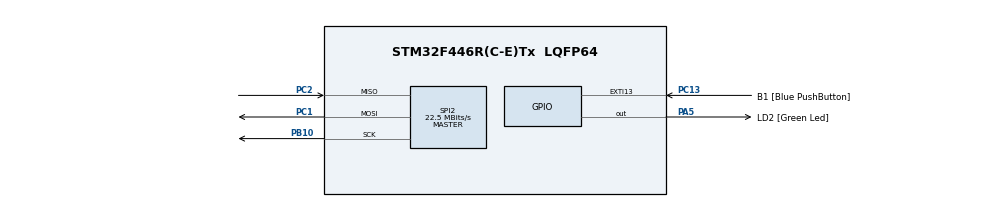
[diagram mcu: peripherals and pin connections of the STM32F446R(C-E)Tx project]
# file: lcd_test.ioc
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Dma.Request0=SPI2_TX
Dma.SPI2_TX.0.Direction=DMA_MEMORY_TO_PERIPH
Dma.SPI2_TX.0.FIFOMode=DMA_FIFOMODE_DISABLE
Dma.SPI2_TX.0.Instance=DMA1_Stream4
Dma.SPI2_TX.0.MemDataAlignment=DMA_MDATAALIGN_HALFWORD
Dma.SPI2_TX.0.MemInc=DMA_MINC_ENABLE
Dma.SPI2_TX.0.Mode=DMA_NORMAL
Dma.SPI2_TX.0.PeriphDataAlignment=DMA_PDATAALIGN_HALFWORD
Dma.SPI2_TX.0.PeriphInc=DMA_PINC_DISABLE
Dma.SPI2_TX.0.Priority=DMA_PRIORITY_MEDIUM
Mcu.Family=STM32F4
Mcu.Name=STM32F446R(C-E)Tx
Mcu.Package=LQFP64
NVIC.DMA1_Stream4_IRQn=true\:0\:0\:false\:false\:true
NVIC.PriorityGroup=NVIC_PRIORITYGROUP_0
PA13.GPIO_Label=TMS
PA13.Signal=SYS_JTMS-SWDIO
PA14.GPIO_Label=TCK
PA14.Signal=SYS_JTCK-SWCLK
PA2.GPIO_Label=USART_TX
PA2.Signal=USART2_TX
PA3.GPIO_Label=USART_RX
PA3.Signal=USART2_RX
PA5.GPIO_Label=LD2 [Green Led]
PA5.Signal=GPIO_Output
PB10.Mode=Full_Duplex_Master
PB10.Signal=SPI2_SCK
PB3.GPIO_Label=SWO
PB3.Signal=SYS_JTDO-SWO
PC1.Mode=Full_Duplex_Master
PC1.Signal=SPI2_MOSI
PC13.GPIO_Label=B1 [Blue PushButton]
PC13.GPIO_ModeDefaultEXTI=GPIO_MODE_IT_FALLING
PC13.Signal=GPXTI13
PC14-OSC32_IN.Signal=RCC_OSC32_IN
PC15-OSC32_OUT.Signal=RCC_OSC32_OUT
PC2.Mode=Full_Duplex_Master
PC2.Signal=SPI2_MISO
PH0-OSC_IN.Signal=RCC_OSC_IN
PH1-OSC_OUT.Signal=RCC_OSC_OUT
ProjectManager.HeapSize=0x200
ProjectManager.StackSize=0x400
ProjectManager.TargetToolchain=SW4STM32
RCC.AHBFreq_Value=180000000
RCC.APB1CLKDivider=RCC_HCLK_DIV4
RCC.APB1Freq_Value=45000000
RCC.APB1TimFreq_Value=90000000
RCC.APB2CLKDivider=RCC_HCLK_DIV2
RCC.APB2Freq_Value=90000000
RCC.APB2TimFreq_Value=180000000
RCC.CortexFreq_Value=180000000
RCC.FLatency-AdvancedSettings=FLASH_LATENCY_5
RCC.HCLKFreq_Value=180000000
RCC.HSE_VALUE=8000000
RCC.HSI_VALUE=16000000
RCC.LSE_VALUE=32768
RCC.PLLM=8
RCC.PLLN=180
RCC.SYSCLKFreq_VALUE=180000000
RCC.SYSCLKSource=RCC_SYSCLKSOURCE_PLLCLK
RCC.USBFreq_Value=180000000
RCC.VCOOutputFreq_Value=360000000
SPI2.BaudRatePrescaler=SPI_BAUDRATEPRESCALER_2
SPI2.CalculateBaudRate=22.5 MBits/s
SPI2.DataSize=SPI_DATASIZE_16BIT
SPI2.Direction=SPI_DIRECTION_2LINES
SPI2.Mode=SPI_MODE_MASTER
SPI2.VirtualType=VM_MASTER
board=NUCLEO-F446RE

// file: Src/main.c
/**
  ******************************************************************************
  * File Name          : main.c
  * Description        : Main program body
  ******************************************************************************
  *
  * COPYRIGHT(c) 2017 STMicroelectronics
  *
  * Redistribution and use in source and binary forms, with or without modification,
  * are permitted provided that the following conditions are met:
  *   1. Redistributions of source code must retain the above copyright notice,
  *      this list of conditions and the following disclaimer.
  *   2. Redistributions in binary form must reproduce the above copyright notice,
  *      this list of conditions and the following disclaimer in the documentation
  *      and/or other materials provided with the distribution.
  *   3. Neither the name of STMicroelectronics nor the names of its contributors
  *      may be used to endorse or promote products derived from this software
  *      without specific prior written permission.
  *
  * THIS SOFTWARE IS PROVIDED BY THE COPYRIGHT HOLDERS AND CONTRIBUTORS "AS IS"
  * AND ANY EXPRESS OR IMPLIED WARRANTIES, INCLUDING, BUT NOT LIMITED TO, THE
  * IMPLIED WARRANTIES OF MERCHANTABILITY AND FITNESS FOR A PARTICULAR PURPOSE ARE
  * DISCLAIMED. IN NO EVENT SHALL THE COPYRIGHT HOLDER OR CONTRIBUTORS BE LIABLE
  * FOR ANY DIRECT, INDIRECT, INCIDENTAL, SPECIAL, EXEMPLARY, OR CONSEQUENTIAL
  * DAMAGES (INCLUDING, BUT NOT LIMITED TO, PROCUREMENT OF SUBSTITUTE GOODS OR
  * SERVICES; LOSS OF USE, DATA, OR PROFITS; OR BUSINESS INTERRUPTION) HOWEVER
  * CAUSED AND ON ANY THEORY OF LIABILITY, WHETHER IN CONTRACT, STRICT LIABILITY,
  * OR TORT (INCLUDING NEGLIGENCE OR OTHERWISE) ARISING IN ANY WAY OUT OF THE USE
  * OF THIS SOFTWARE, EVEN IF ADVISED OF THE POSSIBILITY OF SUCH DAMAGE.
  *
  ******************************************************************************
  */
#include "main.h"
#include "stm32f4xx_hal.h"

SPI_HandleTypeDef hspi2;
DMA_HandleTypeDef hdma_spi2_tx;

/* USER CODE BEGIN PV */
/* Private variables ---------------------------------------------------------*/

/* USER CODE END PV */

void SystemClock_Config(void);
void Error_Handler(void);
static void MX_GPIO_Init(void);
static void MX_DMA_Init(void);
static void MX_SPI2_Init(void);

/* USER CODE BEGIN PFP */
/* Private function prototypes -----------------------------------------------*/

/* USER CODE END PFP */

/* USER CODE BEGIN 0 */
void toggleLED(void);
/* USER CODE END 0 */

int main(void)
{

  /* MCU Configuration----------------------------------------------------------*/

  /* Reset of all peripherals, Initializes the Flash interface and the Systick. */
  HAL_Init();

  /* Configure the system clock */
  SystemClock_Config();

  /* Initialize all configured peripherals */
  MX_GPIO_Init();
  MX_DMA_Init();
  MX_SPI2_Init();

  /* Infinite loop */
  while (1)
  {
  /* USER CODE BEGIN 3 */
    while(1){
      appmain();
    }
  }
  /* USER CODE END 3 */

}

/** System Clock Configuration
*/
void SystemClock_Config(void)
{

  RCC_OscInitTypeDef RCC_OscInitStruct;
  RCC_ClkInitTypeDef RCC_ClkInitStruct;

    /**Configure the main internal regulator output voltage
    */
  __HAL_RCC_PWR_CLK_ENABLE();

  __HAL_PWR_VOLTAGESCALING_CONFIG(PWR_REGULATOR_VOLTAGE_SCALE1);

    /**Initializes the CPU, AHB and APB busses clocks
    */
  RCC_OscInitStruct.OscillatorType = RCC_OSCILLATORTYPE_HSI;
  RCC_OscInitStruct.HSIState = RCC_HSI_ON;
  RCC_OscInitStruct.HSICalibrationValue = 16;
  RCC_OscInitStruct.PLL.PLLState = RCC_PLL_ON;
  RCC_OscInitStruct.PLL.PLLSource = RCC_PLLSOURCE_HSI;
  RCC_OscInitStruct.PLL.PLLM = 8;
  RCC_OscInitStruct.PLL.PLLN = 250;
  RCC_OscInitStruct.PLL.PLLP = RCC_PLLP_DIV2;
  RCC_OscInitStruct.PLL.PLLQ = 2;
  RCC_OscInitStruct.PLL.PLLR = 2;
  if (HAL_RCC_OscConfig(&RCC_OscInitStruct) != HAL_OK)
  {
    Error_Handler();
  }

    /**Activate the Over-Drive mode
    */
  if (HAL_PWREx_EnableOverDrive() != HAL_OK)
  {
    Error_Handler();
  }

    /**Initializes the CPU, AHB and APB busses clocks
    */
  RCC_ClkInitStruct.ClockType = RCC_CLOCKTYPE_HCLK|RCC_CLOCKTYPE_SYSCLK
                              |RCC_CLOCKTYPE_PCLK1|RCC_CLOCKTYPE_PCLK2;
  RCC_ClkInitStruct.SYSCLKSource = RCC_SYSCLKSOURCE_PLLCLK;
  RCC_ClkInitStruct.AHBCLKDivider = RCC_SYSCLK_DIV1;
  RCC_ClkInitStruct.APB1CLKDivider = RCC_HCLK_DIV4;
  RCC_ClkInitStruct.APB2CLKDivider = RCC_HCLK_DIV2;

  if (HAL_RCC_ClockConfig(&RCC_ClkInitStruct, FLASH_LATENCY_5) != HAL_OK)
  {
    Error_Handler();
  }

    /**Configure the Systick interrupt time
    */
  HAL_SYSTICK_Config(HAL_RCC_GetHCLKFreq()/1000);

    /**Configure the Systick
    */
  HAL_SYSTICK_CLKSourceConfig(SYSTICK_CLKSOURCE_HCLK);

  /* SysTick_IRQn interrupt configuration */
  HAL_NVIC_SetPriority(SysTick_IRQn, 0, 0);
}

/* SPI2 init function */
static void MX_SPI2_Init(void)
{
  hspi2.Instance = SPI2;
  hspi2.Init.Mode = SPI_MODE_MASTER;
  hspi2.Init.Direction = SPI_DIRECTION_2LINES;
  hspi2.Init.DataSize = SPI_DATASIZE_8BIT;
  hspi2.Init.CLKPolarity = SPI_POLARITY_HIGH;
  hspi2.Init.CLKPhase = SPI_PHASE_2EDGE;
  hspi2.Init.NSS = SPI_NSS_SOFT;
  hspi2.Init.BaudRatePrescaler = SPI_BAUDRATEPRESCALER_2;
  hspi2.Init.FirstBit = SPI_FIRSTBIT_MSB;
  hspi2.Init.TIMode = SPI_TIMODE_DISABLE;
  hspi2.Init.CRCCalculation = SPI_CRCCALCULATION_DISABLE;
  hspi2.Init.CRCPolynomial = 10;
  if (HAL_SPI_Init(&hspi2) != HAL_OK)
  {
    Error_Handler();
  }
}

static void MX_DMA_Init(void)
{
  /* DMA controller clock enable */
  __HAL_RCC_DMA1_CLK_ENABLE();

  /* DMA interrupt init */
  /* DMA1_Stream4_IRQn interrupt configuration */
  HAL_NVIC_SetPriority(DMA1_Stream4_IRQn, 0, 0);
  HAL_NVIC_EnableIRQ(DMA1_Stream4_IRQn);

}

/** Configure pins as
        * Analog
        * Input
        * Output
        * EVENT_OUT
        * EXTI
     PA2   ------> USART2_TX
     PA3   ------> USART2_RX
*/
static void MX_GPIO_Init(void)
{

  GPIO_InitTypeDef GPIO_InitStruct;

  /* GPIO Ports Clock Enable */
  __HAL_RCC_GPIOC_CLK_ENABLE();
  __HAL_RCC_GPIOH_CLK_ENABLE();
  __HAL_RCC_GPIOA_CLK_ENABLE();
  __HAL_RCC_GPIOB_CLK_ENABLE();

  /*Configure GPIO pin Output Level */
  HAL_GPIO_WritePin(LD2_GPIO_Port, LD2_Pin, GPIO_PIN_RESET);

  /*Configure GPIO pin : B1_Pin */
  GPIO_InitStruct.Pin = B1_Pin;
  GPIO_InitStruct.Mode = GPIO_MODE_IT_FALLING;
  GPIO_InitStruct.Pull = GPIO_NOPULL;
  HAL_GPIO_Init(B1_GPIO_Port, &GPIO_InitStruct);

  /*Configure GPIO pins : USART_TX_Pin USART_RX_Pin */
  GPIO_InitStruct.Pin = USART_TX_Pin|USART_RX_Pin;
  GPIO_InitStruct.Mode = GPIO_MODE_AF_PP;
  GPIO_InitStruct.Pull = GPIO_NOPULL;
  GPIO_InitStruct.Speed = GPIO_SPEED_FREQ_VERY_HIGH;
  GPIO_InitStruct.Alternate = GPIO_AF7_USART2;
  HAL_GPIO_Init(GPIOA, &GPIO_InitStruct);

  /*Configure GPIO pin : LD2_Pin */
  GPIO_InitStruct.Pin = LD2_Pin;
  GPIO_InitStruct.Mode = GPIO_MODE_OUTPUT_PP;
  GPIO_InitStruct.Pull = GPIO_NOPULL;
  GPIO_InitStruct.Speed = GPIO_SPEED_FREQ_LOW;
  HAL_GPIO_Init(LD2_GPIO_Port, &GPIO_InitStruct);

}

/* USER CODE BEGIN 4 */
void toggleLED(void){
  HAL_GPIO_TogglePin(LD2_GPIO_Port,LD2_Pin);
}
/* USER CODE END 4 */

void Error_Handler(void)
{
  while(1)
  {
  }
}

/************************ (C) COPYRIGHT STMicroelectronics *****END OF FILE****/
